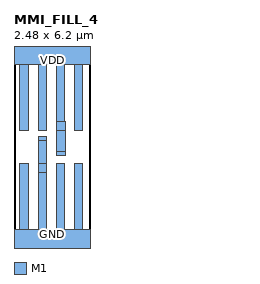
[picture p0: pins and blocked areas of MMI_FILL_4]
MACRO MMI_FILL_4
	CLASS CORE ;
	FOREIGN MMI_FILL_4 0 0 ;
	SIZE 2.48 BY 6.2 ;
	SYMMETRY X Y ;
	SITE CORE1 ;
	PIN GND
		DIRECTION inout ;
		USE GROUND ;
		PORT
			LAYER M1 ;
			RECT 0.79 3.31 1.07 3.445 ;
			LAYER M1 ;
			RECT 0.79 2.555 1.075 3.31 ;
			LAYER M1 ;
			RECT 0.195 0.42 0.475 2.555 ;
			LAYER M1 ;
			RECT 0.785 2.27 1.075 2.555 ;
			LAYER M1 ;
			RECT 0.785 0.42 1.065 2.27 ;
			LAYER M1 ;
			RECT 1.375 0.42 1.655 2.555 ;
			LAYER M1 ;
			RECT 1.965 0.42 2.245 2.555 ;
			LAYER M1 ;
			RECT 0 -0.42 2.48 0.42 ;
		END
	END GND
	PIN VDD
		DIRECTION inout ;
		USE POWER ;
		PORT
			LAYER M1 ;
			RECT 0 5.78 2.48 6.62 ;
			LAYER M1 ;
			RECT 0.195 3.645 0.475 5.78 ;
			LAYER M1 ;
			RECT 0.785 3.645 1.065 5.78 ;
			LAYER M1 ;
			RECT 1.375 3.93 1.655 5.78 ;
			LAYER M1 ;
			RECT 1.375 3.645 1.675 3.93 ;
			LAYER M1 ;
			RECT 1.965 3.645 2.245 5.78 ;
			LAYER M1 ;
			RECT 1.39 2.955 1.675 3.645 ;
			LAYER M1 ;
			RECT 1.395 2.835 1.675 2.955 ;
		END
	END VDD
	OBS
	END
END MMI_FILL_4
